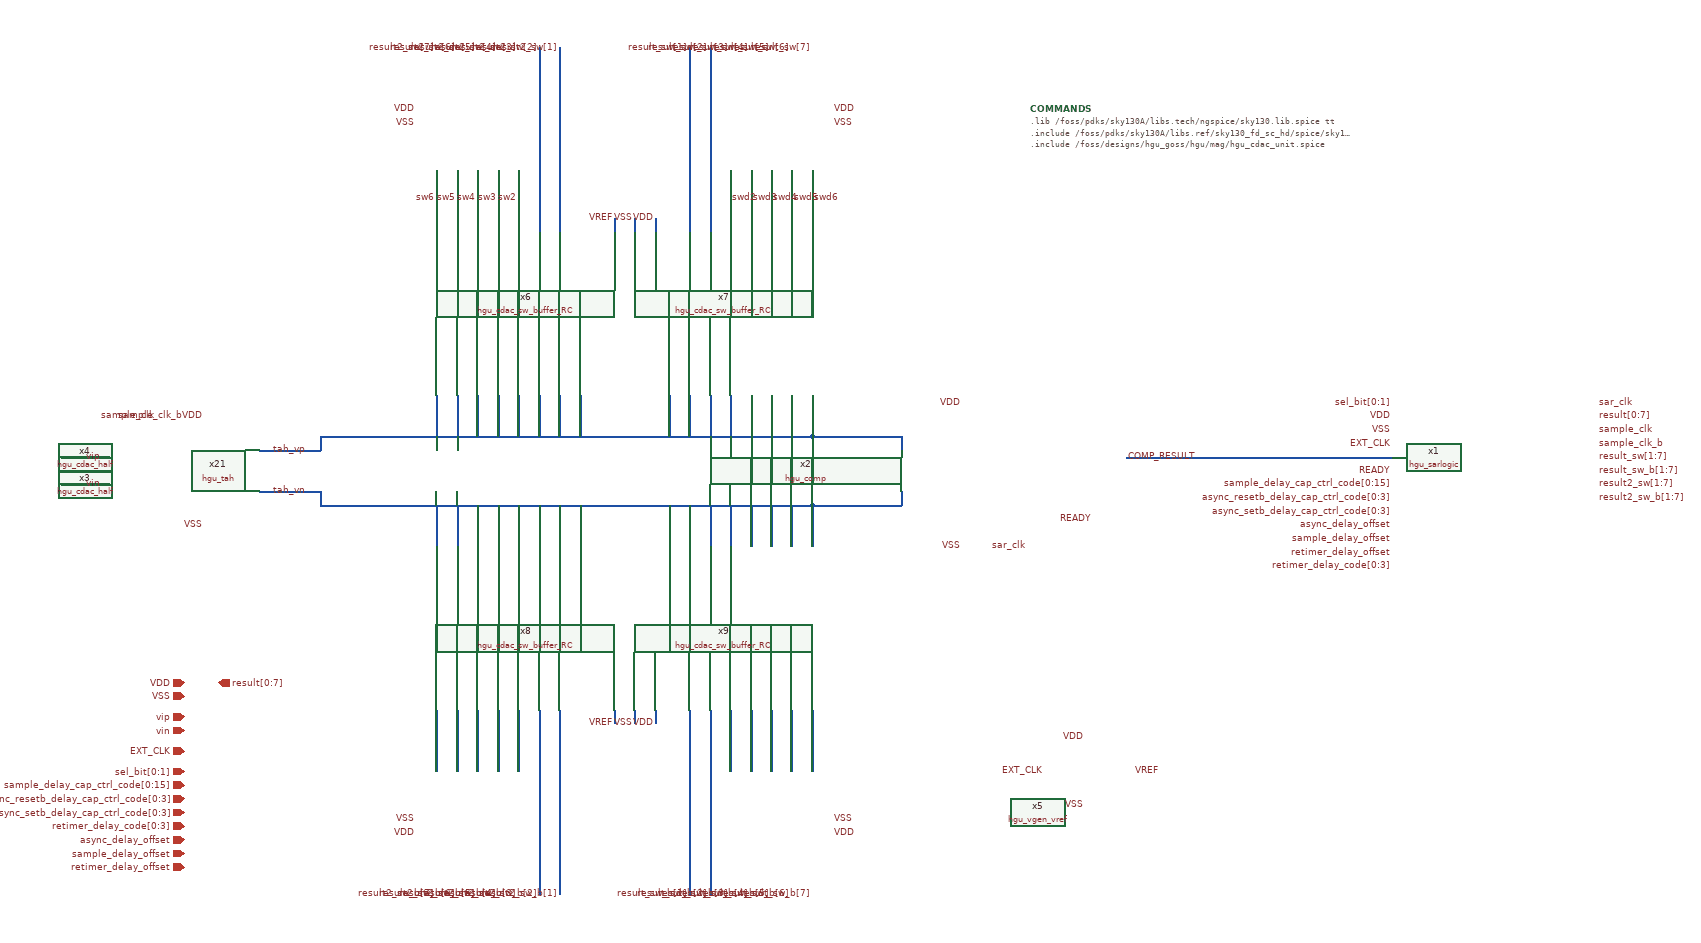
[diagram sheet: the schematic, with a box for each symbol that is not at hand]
v {xschem version=3.4.0 file_version=1.2
}
G {}
K {}
V {}
S {}
E {}
N 1060 -1010 1060 -950 {
lab=tah_vp}
N 1090 -1010 1090 -950 {
lab=tah_vp}
N 1120 -1010 1120 -950 {
lab=tah_vp}
N 1150 -1010 1150 -950 {
lab=tah_vp}
N 1180 -1010 1180 -950 {
lab=tah_vp}
N 1210 -1010 1210 -950 {
lab=tah_vp}
N 1240 -1010 1240 -950 {
lab=tah_vp}
N 1270 -1010 1270 -950 {
lab=tah_vp}
N 1400 -1010 1400 -950 {
lab=tah_vp}
N 1430 -1010 1430 -950 {
lab=tah_vp}
N 1460 -1010 1460 -950 {
lab=tah_vp}
N 1490 -1010 1490 -950 {
lab=tah_vp}
N 1520 -1010 1520 -950 {
lab=tah_vp}
N 1550 -1010 1550 -950 {
lab=tah_vp}
N 1580 -1010 1580 -950 {
lab=tah_vp}
N 1610 -1010 1610 -950 {
lab=tah_vp}
N 1060 -850 1060 -790 {
lab=tah_vn}
N 1090 -850 1090 -790 {
lab=tah_vn}
N 1120 -850 1120 -790 {
lab=tah_vn}
N 1150 -850 1150 -790 {
lab=tah_vn}
N 1180 -850 1180 -790 {
lab=tah_vn}
N 1210 -850 1210 -790 {
lab=tah_vn}
N 1240 -850 1240 -790 {
lab=tah_vn}
N 1270 -850 1270 -790 {
lab=tah_vn}
N 1400 -850 1400 -790 {
lab=tah_vn}
N 1430 -850 1430 -790 {
lab=tah_vn}
N 1460 -850 1460 -790 {
lab=tah_vn}
N 1490 -850 1490 -790 {
lab=tah_vn}
N 1520 -850 1520 -790 {
lab=tah_vn}
N 1550 -850 1550 -790 {
lab=tah_vn}
N 1580 -850 1580 -790 {
lab=tah_vn}
N 1610 -850 1610 -790 {
lab=tah_vn}
N 910 -950 1610 -950 {
lab=tah_vp}
N 910 -850 1610 -850 {
lab=tah_vn}
N 1610 -950 1740 -950 {
lab=tah_vp}
N 1610 -850 1740 -850 {
lab=tah_vn}
N 1060 -1340 1060 -1250 {
lab=sw6}
N 1090 -1340 1090 -1250 {
lab=sw5}
N 1120 -1340 1120 -1250 {
lab=sw4}
N 1150 -1340 1150 -1250 {
lab=sw3}
N 1180 -1340 1180 -1250 {
lab=sw2}
N 1210 -1340 1210 -1250 {
lab=result2_sw[2]}
N 1240 -1340 1240 -1250 {
lab=result2_sw[1]}
N 1430 -1340 1430 -1250 {
lab=result_sw[1]}
N 1460 -1340 1460 -1250 {
lab=result_sw[2]}
N 1490 -1340 1490 -1250 {
lab=swd2}
N 1520 -1340 1520 -1250 {
lab=swd3}
N 1550 -1340 1550 -1250 {
lab=swd4}
N 1580 -1340 1580 -1250 {
lab=swd5}
N 1610 -1340 1610 -1250 {
lab=swd6}
N 1240 -550 1240 -460 {
lab=result2_sw_b[1]}
N 1210 -550 1210 -460 {
lab=result2_sw_b[2]}
N 1180 -550 1180 -460 {
lab=#net1}
N 1150 -550 1150 -460 {
lab=#net2}
N 1120 -550 1120 -460 {
lab=#net3}
N 1090 -550 1090 -460 {
lab=#net4}
N 1060 -550 1060 -460 {
lab=#net5}
N 1610 -550 1610 -460 {
lab=#net6}
N 1580 -550 1580 -460 {
lab=#net7}
N 1550 -550 1550 -460 {
lab=#net8}
N 1520 -550 1520 -460 {
lab=#net9}
N 1490 -550 1490 -460 {
lab=#net10}
N 1460 -550 1460 -460 {
lab=result_sw_b[2]}
N 1430 -550 1430 -460 {
lab=result_sw_b[1]}
N 1320 -1270 1320 -1250 {
lab=VREF}
N 1350 -1270 1350 -1250 {
lab=VSS}
N 800 -930 880 -930 {
lab=tah_vp}
N 800 -870 840 -870 {
lab=tah_vn}
N 510 -880 580 -880 {
lab=vin}
N 880 -930 890 -930 {
lab=tah_vp}
N 890 -950 890 -930 {
lab=tah_vp}
N 890 -950 910 -950 {
lab=tah_vp}
N 840 -870 890 -870 {
lab=tah_vn}
N 890 -870 890 -850 {
lab=tah_vn}
N 890 -850 910 -850 {
lab=tah_vn}
N 1320 -550 1320 -530 {
lab=VREF}
N 1350 -550 1350 -530 {
lab=VSS}
N 1740 -950 1740 -930 {
lab=tah_vp}
N 1740 -870 1740 -850 {
lab=tah_vn}
N 2070 -920 2460 -920 {
lab=COMP_RESULT}
N 510 -920 580 -920 {
lab=vip}
N 1380 -1270 1380 -1250 {
lab=VDD}
N 1380 -550 1380 -530 {
lab=VDD}
N 1210 -1520 1210 -1340 {
lab=result2_sw[2]}
N 1240 -1520 1240 -1340 {
lab=result2_sw[1]}
N 1430 -1520 1430 -1340 {
lab=result_sw[1]}
N 1460 -1520 1460 -1340 {
lab=result_sw[2]}
N 1430 -460 1430 -280 {
lab=result_sw_b[1]}
N 1460 -460 1460 -280 {
lab=result_sw_b[2]}
N 1210 -460 1210 -280 {
lab=result2_sw_b[2]}
N 1240 -460 1240 -280 {
lab=result2_sw_b[1]}
C {hgu_sarlogic.sym} 2610 -880 0 0 {name=x1}
C {hgu_comp.sym} 1910 -900 0 0 {name=x2}
C {hgu_cdac_half.sym} 510 -890 0 0 {name=x3}
C {hgu_cdac_half.sym} 510 -910 2 1 {name=x4}
C {devices/lab_wire.sym} 1350 -530 2 1 {name=p4 sig_type=std_logic lab=VSS}
C {hgu_tah.sym} 650 -900 0 0 {name=x21}
C {devices/lab_wire.sym} 570 -920 0 0 {name=p29 sig_type=std_logic lab=vip

}
C {devices/lab_wire.sym} 870 -870 0 0 {name=p30 sig_type=std_logic lab=tah_vn
}
C {devices/lab_wire.sym} 870 -930 0 0 {name=p31 sig_type=std_logic lab=tah_vp
}
C {devices/lab_wire.sym} 570 -880 0 0 {name=p32 sig_type=std_logic lab=vin

}
C {devices/lab_wire.sym} 1320 -1270 0 0 {name=p1 sig_type=std_logic lab=VREF}
C {devices/lab_wire.sym} 1320 -530 2 1 {name=p3 sig_type=std_logic lab=VREF}
C {devices/lab_wire.sym} 1350 -1270 0 0 {name=p7 sig_type=std_logic lab=VSS}
C {devices/lab_pin.sym} 2070 -920 2 0 {name=p2 sig_type=std_logic lab=COMP_RESULT}
C {devices/lab_pin.sym} 1970 -830 2 0 {name=p33 sig_type=std_logic lab=READY}
C {devices/lab_pin.sym} 1870 -790 2 0 {name=p34 sig_type=std_logic lab=sar_clk}
C {devices/lab_pin.sym} 1830 -790 0 0 {name=p39 sig_type=std_logic lab=VSS}
C {devices/lab_pin.sym} 1830 -1000 0 0 {name=p40 sig_type=std_logic lab=VDD}
C {devices/noconn.sym} 2070 -880 2 0 {name=l3}
C {devices/lab_pin.sym} 2460 -980 0 0 {name=p41 sig_type=std_logic lab=VDD}
C {devices/lab_pin.sym} 2460 -960 0 0 {name=p42 sig_type=std_logic lab=VSS}
C {devices/lab_pin.sym} 2460 -940 0 0 {name=p43 sig_type=std_logic lab=EXT_CLK}
C {devices/lab_pin.sym} 2460 -900 0 0 {name=p45 sig_type=std_logic lab=READY}
C {devices/lab_pin.sym} 2760 -1000 2 0 {name=p65 sig_type=std_logic lab=sar_clk}
C {devices/lab_pin.sym} 2760 -980 2 0 {name=p67 sig_type=std_logic lab=result[0:7]}
C {devices/lab_pin.sym} 2760 -960 2 0 {name=p69 sig_type=std_logic lab=sample_clk}
C {devices/lab_pin.sym} 2460 -1000 0 0 {name=p71 sig_type=std_logic lab=sel_bit[0:1]}
C {devices/lab_pin.sym} 2460 -880 0 0 {name=p72 sig_type=std_logic lab=sample_delay_cap_ctrl_code[0:15]}
C {devices/lab_pin.sym} 2760 -940 2 0 {name=p8 sig_type=std_logic lab=sample_clk_b}
C {devices/lab_pin.sym} 650 -980 1 0 {name=p10 sig_type=std_logic lab=sample_clk}
C {devices/lab_pin.sym} 690 -980 1 0 {name=p11 sig_type=std_logic lab=sample_clk_b}
C {devices/lab_pin.sym} 2760 -920 2 0 {name=p81 sig_type=std_logic lab=result_sw[1:7]}
C {devices/lab_pin.sym} 2760 -900 2 0 {name=p82 sig_type=std_logic lab=result_sw_b[1:7]}
C {devices/lab_pin.sym} 2760 -880 2 0 {name=p83 sig_type=std_logic lab=result2_sw[1:7]}
C {devices/lab_pin.sym} 2760 -860 2 0 {name=p84 sig_type=std_logic lab=result2_sw_b[1:7]}
C {devices/lab_pin.sym} 1610 -1520 3 1 {name=p36 sig_type=std_logic lab=result_sw[7]}
C {devices/lab_pin.sym} 1580 -1520 3 1 {name=p37 sig_type=std_logic lab=result_sw[6]}
C {devices/lab_pin.sym} 1550 -1520 3 1 {name=p38 sig_type=std_logic lab=result_sw[5]}
C {devices/lab_pin.sym} 1520 -1520 3 1 {name=p44 sig_type=std_logic lab=result_sw[4]}
C {devices/lab_pin.sym} 1490 -1520 3 1 {name=p46 sig_type=std_logic lab=result_sw[3]}
C {devices/lab_pin.sym} 1460 -1520 3 1 {name=p47 sig_type=std_logic lab=result_sw[2]}
C {devices/lab_pin.sym} 1430 -1520 3 1 {name=p48 sig_type=std_logic lab=result_sw[1]}
C {devices/lab_pin.sym} 1060 -1520 1 0 {name=p49 sig_type=std_logic lab=result2_sw[7]}
C {devices/lab_pin.sym} 1090 -1520 1 0 {name=p50 sig_type=std_logic lab=result2_sw[6]}
C {devices/lab_pin.sym} 1120 -1520 1 0 {name=p51 sig_type=std_logic lab=result2_sw[5]}
C {devices/lab_pin.sym} 1150 -1520 1 0 {name=p52 sig_type=std_logic lab=result2_sw[4]}
C {devices/lab_pin.sym} 1180 -1520 1 0 {name=p53 sig_type=std_logic lab=result2_sw[3]}
C {devices/lab_pin.sym} 1210 -1520 1 0 {name=p54 sig_type=std_logic lab=result2_sw[2]}
C {devices/lab_pin.sym} 1240 -1520 1 0 {name=p55 sig_type=std_logic lab=result2_sw[1]}
C {hgu_cdac_sw_buffer_RC.sym} 1150 -1420 0 0 {name=x6}
C {hgu_cdac_sw_buffer_RC.sym} 1520 -1420 0 1 {name=x7}
C {devices/lab_wire.sym} 1060 -1300 0 0 {name=p56 sig_type=std_logic lab=sw6
}
C {devices/lab_wire.sym} 1090 -1300 0 0 {name=p57 sig_type=std_logic lab=sw5
}
C {devices/lab_wire.sym} 1120 -1300 0 0 {name=p58 sig_type=std_logic lab=sw4
}
C {devices/lab_wire.sym} 1150 -1300 0 0 {name=p59 sig_type=std_logic lab=sw3
}
C {devices/lab_wire.sym} 1180 -1300 0 0 {name=p60 sig_type=std_logic lab=sw2
}
C {devices/lab_pin.sym} 1610 -280 1 1 {name=p16 sig_type=std_logic lab=result_sw_b[7]}
C {devices/lab_pin.sym} 1580 -280 1 1 {name=p18 sig_type=std_logic lab=result_sw_b[6]}
C {devices/lab_pin.sym} 1550 -280 1 1 {name=p20 sig_type=std_logic lab=result_sw_b[5]}
C {devices/lab_pin.sym} 1520 -280 1 1 {name=p22 sig_type=std_logic lab=result_sw_b[4]}
C {devices/lab_pin.sym} 1490 -280 1 1 {name=p24 sig_type=std_logic lab=result_sw_b[3]}
C {devices/lab_pin.sym} 1460 -280 1 1 {name=p76 sig_type=std_logic lab=result_sw_b[2]}
C {devices/lab_pin.sym} 1430 -280 1 1 {name=p80 sig_type=std_logic lab=result_sw_b[1]}
C {devices/lab_pin.sym} 1060 -280 3 0 {name=p92 sig_type=std_logic lab=result2_sw_b[7]}
C {devices/lab_pin.sym} 1090 -280 3 0 {name=p93 sig_type=std_logic lab=result2_sw_b[6]}
C {devices/lab_pin.sym} 1120 -280 3 0 {name=p94 sig_type=std_logic lab=result2_sw_b[5]}
C {devices/lab_pin.sym} 1150 -280 3 0 {name=p95 sig_type=std_logic lab=result2_sw_b[4]}
C {devices/lab_pin.sym} 1180 -280 3 0 {name=p96 sig_type=std_logic lab=result2_sw_b[3]}
C {devices/lab_pin.sym} 1210 -280 3 0 {name=p97 sig_type=std_logic lab=result2_sw_b[2]}
C {devices/lab_pin.sym} 1240 -280 3 0 {name=p98 sig_type=std_logic lab=result2_sw_b[1]}
C {hgu_cdac_sw_buffer_RC.sym} 1150 -380 2 1 {name=x8}
C {hgu_cdac_sw_buffer_RC.sym} 1520 -380 2 0 {name=x9}
C {devices/lab_wire.sym} 1380 -1270 0 0 {name=p14 sig_type=std_logic lab=VDD}
C {devices/lab_wire.sym} 1380 -530 2 1 {name=p17 sig_type=std_logic lab=VDD}
C {devices/lab_wire.sym} 1610 -1300 0 1 {name=p19 sig_type=std_logic lab=swd6
}
C {devices/lab_wire.sym} 1580 -1300 0 1 {name=p21 sig_type=std_logic lab=swd5
}
C {devices/lab_wire.sym} 1550 -1300 0 1 {name=p23 sig_type=std_logic lab=swd4
}
C {devices/lab_wire.sym} 1520 -1300 0 1 {name=p28 sig_type=std_logic lab=swd3
}
C {devices/lab_wire.sym} 1490 -1300 0 1 {name=p63 sig_type=std_logic lab=swd2
}
C {devices/lab_pin.sym} 2460 -860 0 0 {name=p12 sig_type=std_logic lab=async_resetb_delay_cap_ctrl_code[0:3]}
C {devices/lab_pin.sym} 2460 -840 0 0 {name=p13 sig_type=std_logic lab=async_setb_delay_cap_ctrl_code[0:3]}
C {devices/lab_pin.sym} 1030 -1430 0 0 {name=p27 sig_type=std_logic lab=VDD}
C {devices/lab_pin.sym} 1030 -1410 0 0 {name=p35 sig_type=std_logic lab=VSS}
C {devices/lab_pin.sym} 1640 -1430 0 1 {name=p61 sig_type=std_logic lab=VDD}
C {devices/lab_pin.sym} 1640 -1410 0 1 {name=p62 sig_type=std_logic lab=VSS}
C {devices/lab_pin.sym} 1640 -370 0 1 {name=p64 sig_type=std_logic lab=VDD}
C {devices/lab_pin.sym} 1640 -390 0 1 {name=p66 sig_type=std_logic lab=VSS}
C {devices/lab_pin.sym} 1030 -370 0 0 {name=p68 sig_type=std_logic lab=VDD}
C {devices/lab_pin.sym} 1030 -390 0 0 {name=p77 sig_type=std_logic lab=VSS}
C {devices/lab_pin.sym} 2460 -760 0 0 {name=p15 sig_type=std_logic lab=retimer_delay_code[0:3]}
C {devices/lab_pin.sym} 720 -820 0 0 {name=p5 sig_type=std_logic lab=VSS}
C {devices/lab_pin.sym} 720 -980 1 0 {name=p6 sig_type=std_logic lab=VDD}
C {devices/ipin.sym} 690 -590 0 0 {name=p74 lab=VDD}
C {devices/ipin.sym} 690 -570 0 0 {name=p78 lab=VSS}
C {devices/opin.sym} 740 -590 0 0 {name=p79 lab=result[0:7]}
C {devices/ipin.sym} 690 -490 0 0 {name=p85 lab=EXT_CLK}
C {devices/ipin.sym} 690 -540 0 0 {name=p86 lab=vip}
C {devices/ipin.sym} 690 -520 0 0 {name=p87 lab=vin}
C {devices/ipin.sym} 690 -460 0 0 {name=p118 lab=sel_bit[0:1]}
C {devices/ipin.sym} 690 -440 0 0 {name=p88 lab=sample_delay_cap_ctrl_code[0:15]}
C {devices/ipin.sym} 690 -420 0 0 {name=p89 lab=async_resetb_delay_cap_ctrl_code[0:3]}
C {devices/ipin.sym} 690 -400 0 0 {name=p90 lab=async_setb_delay_cap_ctrl_code[0:3]}
C {devices/ipin.sym} 690 -360 0 0 {name=p91 lab=async_delay_offset}
C {devices/ipin.sym} 690 -340 0 0 {name=p99 lab=sample_delay_offset}
C {devices/ipin.sym} 690 -380 0 0 {name=p100 lab=retimer_delay_code[0:3]}
C {devices/lab_pin.sym} 2460 -820 0 0 {name=p25 sig_type=std_logic lab=async_delay_offset}
C {devices/lab_pin.sym} 2460 -800 0 0 {name=p26 sig_type=std_logic lab=sample_delay_offset}
C {devices/lab_pin.sym} 2460 -780 0 0 {name=p101 sig_type=std_logic lab=retimer_delay_offset}
C {devices/ipin.sym} 690 -320 0 0 {name=p102 lab=retimer_delay_offset}
C {devices/lab_wire.sym} 2080 -460 2 0 {name=p9 sig_type=std_logic lab=VREF}
C {/foss/designs/hgu_goss/hgu/xschem/hgu_vgen_vref.sym} 1940 -400 0 0 {name=x5}
C {devices/lab_pin.sym} 1950 -460 2 1 {name=p70 sig_type=std_logic lab=EXT_CLK}
C {devices/lab_pin.sym} 2010 -510 0 0 {name=p73 sig_type=std_logic lab=VDD}
C {devices/lab_pin.sym} 2010 -410 0 0 {name=p75 sig_type=std_logic lab=VSS}
C {devices/simulator_commands_shown.sym} 1930 -1430 0 0 {name=COMMANDS
simulator=ngspice
only_toplevel=false 
value="
.lib /foss/pdks/sky130A/libs.tech/ngspice/sky130.lib.spice tt
.include /foss/pdks/sky130A/libs.ref/sky130_fd_sc_hd/spice/sky130_fd_sc_hd.spice
.include /foss/designs/hgu_goss/hgu/mag/hgu_cdac_unit.spice
"}
